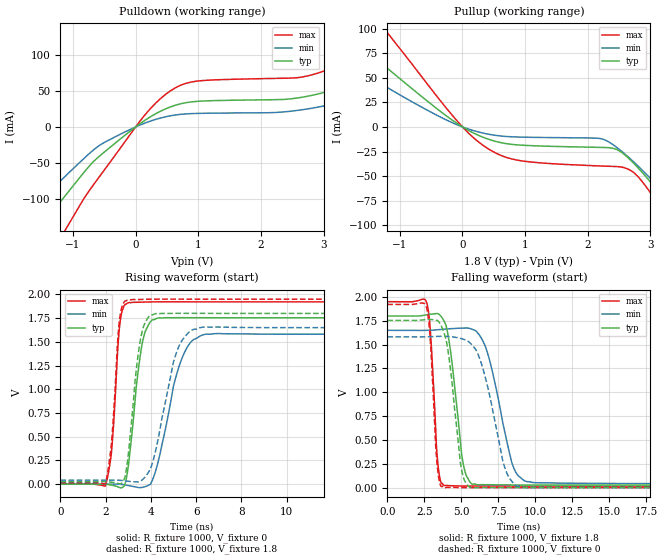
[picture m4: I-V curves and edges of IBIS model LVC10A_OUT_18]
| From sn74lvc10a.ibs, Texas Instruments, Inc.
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[Model]   LVC10A_OUT_18
Model_type  Output
Vref =   0
Rref =   1000
Cref =   30p
Vmeas =   0.9
| variable   typ   min   max
C_comp   6.87pF   4.46pF   11.31pF
| C_pullup   5.90pF   4.46pF   6.82pF
| C_pulldown   7.84pF   4.65pF   11.31pF
[Temperature Range]   40   100   -40
| Ambient temperature   25   85   -40
[Voltage range]   1.8   1.65   1.95
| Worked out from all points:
|   slope of the pulldown table from 0 to 0.27 V, typ, clamps not added: 17.1 ohm
|   slope of the pullup table from 0 to 0.27 V, typ, clamps not added: 29.9 ohm
|   rising waveform, R_fixture 1000, V_fixture 0: 20-80 % time 481ps typ, 877ps min, 294ps max; typ from 0 V to 1.75 V
|   falling waveform, R_fixture 1000, V_fixture 1.8: 20-80 % time 740ps typ, 1.33ns min, 389ps max; typ from 1.8 V to 0.027 V
|   rising waveform, R_fixture 1000, V_fixture 1.8: 20-80 % time 454ps typ, 830ps min, 301ps max; typ from 0.027 V to 1.8 V
|   falling waveform, R_fixture 1000, V_fixture 0: 20-80 % time 746ps typ, 1.33ns min, 384ps max; typ from 1.75 V to 0 V
[Pulldown]
| LVC10A_OUT_18
|   Voltage   I(typ)   I(min)   I(max)
-5.5V     -559.1mA   -452.2mA   -710.9mA
-2.18V    -208.5mA   -158.8mA   -285.4mA
-1.865V   -175.2mA   -131.6mA   -244.5mA
-1.48V    -133.9mA   -98.56mA   -193.1mA
-1.07V    -89.31mA   -63.76mA   -134.9mA
70mV      4.491mA    2.617mA    8.125mA
615mV     29.45mA    16.27mA    53.12mA
2.815V    43.69mA    25.92mA    72.1mA
4.325V    93.52mA    64.21mA    142.7mA
5.155V    134.5mA    96.03mA    199.6mA
6.155V    191.3mA    141.3mA    276.1mA
11V       510.2mA    405.2mA    689.3mA
[Pullup]
| LVC10A_OUT_18
|   Voltage   I(typ)   I(min)   I(max)
-5.5V     324.9mA    249.5mA    454.8mA
-2.68V    143.9mA    103mA      216.3mA
-2.015V   104.9mA    73.15mA    161.8mA
-1.32V    66.21mA    44.72mA    105.6mA
360mV     -11.3mA    -6.711mA   -20.18mA
985mV     -18.72mA   -10.42mA   -34.9mA
2.465V    -23.02mA   -20.97mA   -40.36mA
2.785V    -40.46mA   -38.76mA   -49.43mA
3.365V    -85.63mA   -77.45mA   -103.2mA
3.56V     -102.6mA   -91.66mA   -124.4mA
3.775V    -122mA     -107.8mA   -148.7mA
11V       -874.4mA   -739.7mA   -1.068A
[Ramp]
| LVC10A_OUT_18
| variable   typ   min   max
dV/dt_r   1.08/5.07E-10   0.97/9.81E-10   1.17/3.07E-10
dV/dt_f   1.08/8.15E-10   0.98/1.41E-09   1.18/4.18E-10
R_load = 1000
[Rising Waveform]
| LVC10A_OUT_18
R_fixture =   1000
C_fixture =   0
L_fixture =   0
V_fixture =   0
V_fixture_min = 0
V_fixture_max = 0
|   Time   V(typ)   V(min)   V(max)
0s        194.2pV    4.892nV    16.26pV
1.985ns   268.2uV    283.8uV    -20.06mV
2.255ns   -9.445mV   329uV      334.9mV
2.63ns    -36.22mV   -1.169mV   1.696V
3ns       192mV      -14.07mV   1.913V
3.615ns   1.483V     -33.44mV   1.919V
4.28ns    1.749V     200.5mV    1.922V
5.295ns   1.755V     1.279V     1.922V
6.32ns    1.755V     1.576V     1.922V
24.99ns   1.754V     1.581V     1.922V
[Falling Waveform]
| LVC10A_OUT_18
R_fixture =   1000
C_fixture =   0
L_fixture =   0
V_fixture =   1.8
V_fixture_min = 1.65
V_fixture_max = 1.95
|   Time   V(typ)   V(min)   V(max)
0s        1.8V       1.65V      1.95V
2.67ns    1.813V     1.65V      1.935V
2.93ns    1.819V     1.651V     1.596V
3.405ns   1.826V     1.656V     267.6mV
3.835ns   1.746V     1.662V     22.73mV
5.085ns   288.2mV    1.673V     16.58mV
5.72ns    37.23mV    1.662V     16.12mV
6.665ns   30.08mV    1.463V     16.19mV
9.27ns    27.45mV    71.42mV    16.27mV
24.99ns   27.13mV    42.43mV    16.27mV
[Rising Waveform]
| LVC10A_OUT_18
R_fixture =   1000
C_fixture =   0
L_fixture =   0
V_fixture =   1.8
V_fixture_min = 1.65
V_fixture_max = 1.95
|   Time   V(typ)   V(min)   V(max)
0s        27.13mV    42.42mV    16.27mV
1.985ns   27.29mV    42.61mV    2.873mV
2.25ns    20.96mV    42.58mV    415.8mV
2.61ns    4.817mV    41.38mV    1.73V
2.98ns    273mV      31.28mV    1.943V
3.545ns   1.535V     33.18mV    1.948V
4.175ns   1.796V     320.9mV    1.95V
5.06ns    1.801V     1.339V     1.95V
5.895ns   1.801V     1.632V     1.95V
24.99ns   1.8V       1.65V      1.95V
[Falling Waveform]
| LVC10A_OUT_18
R_fixture =   1000
C_fixture =   0
L_fixture =   0
V_fixture =   0
V_fixture_min = 0
V_fixture_max = 0
|   Time   V(typ)   V(min)   V(max)
0s        1.754V     1.581V     1.922V
2.65ns    1.763V     1.582V     1.889V
2.91ns    1.764V     1.583V     1.532V
3.335ns   1.754V     1.586V     296.4mV
3.65ns    1.694V     1.587V     9.418mV
4.155ns   1.377V     1.585V     1.461mV
4.985ns   215.1mV    1.564V     190.5uV
5.57ns    3.822mV    1.52V      -223.1uV
8.745ns   197.7uV    16.73mV    -1.986uV
24.99ns   5.329nV    2.403uV    13.48nV
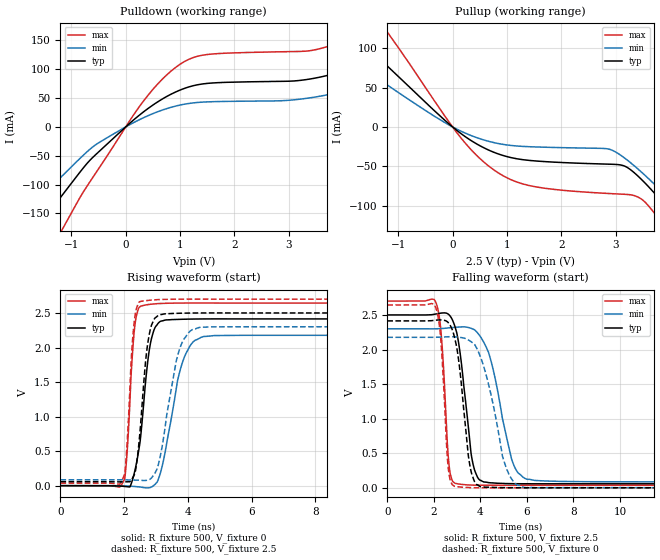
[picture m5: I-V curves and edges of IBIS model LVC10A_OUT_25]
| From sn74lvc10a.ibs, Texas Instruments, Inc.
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[Model]   LVC10A_OUT_25
Model_type  Output
Vref =   0
Rref =   500
Cref =   30p
Vmeas =   1.25
| variable   typ   min   max
C_comp   6.67pF   4.38pF   10.22pF
| C_pullup   5.84pF   4.42pF   6.92pF
| C_pulldown   7.51pF   4.38pF   10.22pF
[Temperature Range]   40   100   -40
| Ambient temperature   25   85   -40
[Voltage range]   2.5   2.3   2.7
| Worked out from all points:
|   slope of the pulldown table from 0 to 0.375 V, typ, clamps not added: 12.7 ohm
|   slope of the pullup table from 0 to 0.375 V, typ, clamps not added: 20 ohm
|   rising waveform, R_fixture 500, V_fixture 0: 20-80 % time 331ps typ, 536ps min, 194ps max; typ from 0 V to 2.41 V
|   falling waveform, R_fixture 500, V_fixture 2.5: 20-80 % time 482ps typ, 825ps min, 265ps max; typ from 2.5 V to 0.057 V
|   rising waveform, R_fixture 500, V_fixture 2.5: 20-80 % time 277ps typ, 487ps min, 187ps max; typ from 0.057 V to 2.5 V
|   falling waveform, R_fixture 500, V_fixture 0: 20-80 % time 446ps typ, 814ps min, 258ps max; typ from 2.41 V to 0 V
[Pulldown]
| LVC10A_OUT_25
|   Voltage   I(typ)   I(min)   I(max)
-5.5V     -598.1mA   -479.8mA   -766.5mA
-2.12V    -233mA     -174.4mA   -327.1mA
-1.575V   -168.1mA   -123.2mA   -244.7mA
-1.15V    -116.2mA   -83.21mA   -174.9mA
-565mV    -49.19mA   -31.72mA   -81.94mA
365mV     28.75mA    17.58mA    49.46mA
1.32V     73.05mA    42.4mA     122.5mA
4V        96.78mA    61.72mA    149.2mA
4.6V      117.3mA    77.78mA    177.9mA
5.77V     171.8mA    120.4mA    253.2mA
7.055V    245.3mA    179.5mA    351.5mA
11V       504.9mA    394.6mA    686.5mA
[Pullup]
| LVC10A_OUT_25
|   Voltage   I(typ)   I(min)   I(max)
-5.5V     363.4mA    279.9mA    508.8mA
-2.6V     169.4mA    122.6mA    251.6mA
-1.815V   117.7mA    83.03mA    179.1mA
-1.37V    88.47mA    61.37mA    136.9mA
170mV     -9.222mA   -5.867mA   -15.32mA
760mV     -32.2mA    -19.89mA   -54.58mA
2.905V    -47.35mA   -28.79mA   -84.65mA
3.45V     -65.04mA   -55.88mA   -90.57mA
3.92V     -100.7mA   -87.07mA   -129.3mA
4.19V     -123.8mA   -106.6mA   -157.6mA
4.495V    -151.4mA   -129.7mA   -191.8mA
11V       -830.2mA   -699.2mA   -1.022A
[Ramp]
| LVC10A_OUT_25
| variable   typ   min   max
dV/dt_r   1.46/3.64E-10   1.32/6.08E-10   1.60/2.04E-10
dV/dt_f   1.48/5.15E-10   1.35/8.62E-10   1.62/2.81E-10
R_load = 500
[Rising Waveform]
| LVC10A_OUT_25
R_fixture =   500
C_fixture =   0
L_fixture =   0
V_fixture =   0
V_fixture_min = 0
V_fixture_max = 0
|   Time   V(typ)   V(min)   V(max)
0s        177.7pV    3.876nV    17.91pV
2ns       -10.49mV   -2.208mV   83.96mV
2.095ns   -14.98mV   -4.472mV   506.8mV
2.325ns   196.9mV    -11.74mV   2.278V
2.61ns    1.177V     -27.32mV   2.61V
2.79ns    1.97V      -29.37mV   2.624V
2.99ns    2.306V     29.2mV     2.633V
3.825ns   2.409V     1.779V     2.644V
4.495ns   2.414V     2.16V      2.644V
24.99ns   2.414V     2.176V     2.644V
[Falling Waveform]
| LVC10A_OUT_25
R_fixture =   500
C_fixture =   0
L_fixture =   0
V_fixture =   2.5
V_fixture_min = 2.3
V_fixture_max = 2.7
|   Time   V(typ)   V(min)   V(max)
0s        2.5V       2.3V       2.7V
2.105ns   2.515V     2.3V       2.664V
2.335ns   2.528V     2.303V     2.14V
2.645ns   2.504V     2.313V     354.2mV
2.92ns    2.317V     2.321V     63.25mV
3.64ns    415.6mV    2.301V     38.86mV
4.14ns    83.94mV    2.108V     35.93mV
5.335ns   59.62mV    420.7mV    35.7mV
5.985ns   57.85mV    125.6mV    35.85mV
24.99ns   57.33mV    84.96mV    35.94mV
[Rising Waveform]
| LVC10A_OUT_25
R_fixture =   500
C_fixture =   0
L_fixture =   0
V_fixture =   2.5
V_fixture_min = 2.3
V_fixture_max = 2.7
|   Time   V(typ)   V(min)   V(max)
0s        57.33mV    84.96mV    35.94mV
1.965ns   55.36mV    84.47mV    110.1mV
2.07ns    55.91mV    83.66mV    459.5mV
2.295ns   138mV      81.31mV    2.281V
2.515ns   887.5mV    77.92mV    2.668V
2.715ns   1.977V     78.23mV    2.68V
2.93ns    2.401V     154.9mV    2.69V
3.715ns   2.496V     1.943V     2.7V
4.365ns   2.5V       2.292V     2.701V
24.99ns   2.5V       2.3V       2.7V
[Falling Waveform]
| LVC10A_OUT_25
R_fixture =   500
C_fixture =   0
L_fixture =   0
V_fixture =   0
V_fixture_min = 0
V_fixture_max = 0
|   Time   V(typ)   V(min)   V(max)
0s        2.414V     2.176V     2.644V
2.085ns   2.424V     2.177V     2.602V
2.305ns   2.428V     2.179V     2.111V
2.615ns   2.39V      2.184V     297.6mV
2.9ns     2.16V      2.183V     20.44mV
3.54ns    336.9mV    2.127V     2.531mV
4ns       16.37mV    1.896V     77.44uV
5.05ns    1.404mV    346.3mV    -293.3uV
5.87ns    -51.98uV   5.991mV    -72.33uV
24.99ns   17.86nV    42.93nV    1.212nV
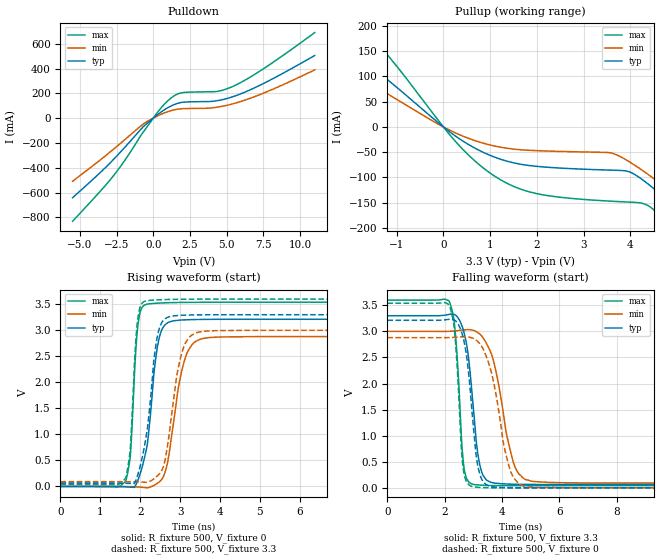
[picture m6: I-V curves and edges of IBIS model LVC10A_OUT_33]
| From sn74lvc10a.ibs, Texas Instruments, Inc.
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[Model]   LVC10A_OUT_33
Model_type  Output
Vref =   0
Rref =   500
Cref =   50p
Vmeas =   1.5
| variable   typ   min   max
C_comp   6.31pF   3.46pF   9.45pF
| C_pullup   5.72pF   3.46pF   7.15pF
| C_pulldown   6.91pF   4.18pF   9.45pF
[Temperature Range]   40   100   -40
| Ambient temperature   25   85   -40
[Voltage range]   3.3   3   3.6
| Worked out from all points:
|   slope of the pulldown table from 0 to 0.495 V, typ, clamps not added: 10.7 ohm
|   slope of the pullup table from 0 to 0.495 V, typ, clamps not added: 15.2 ohm
|   rising waveform, R_fixture 500, V_fixture 0: 20-80 % time 275ps typ, 355ps min, 146ps max; typ from 0 V to 3.21 V
|   falling waveform, R_fixture 500, V_fixture 3.3: 20-80 % time 349ps typ, 600ps min, 226ps max; typ from 3.3 V to 0.065 V
|   rising waveform, R_fixture 500, V_fixture 3.3: 20-80 % time 290ps typ, 331ps min, 145ps max; typ from 0.065 V to 3.3 V
|   falling waveform, R_fixture 500, V_fixture 0: 20-80 % time 342ps typ, 583ps min, 217ps max; typ from 3.21 V to 0 V
[Pulldown]
| LVC10A_OUT_33
|   Voltage   I(typ)   I(min)   I(max)
-5.5V     -642.1mA   -509.2mA   -832.1mA
-3.645V   -442.6mA   -340.3mA   -594.1mA
-2.71V    -333.2mA   -250.5mA   -464.6mA
-1.885V   -228.4mA   -168.1mA   -330.7mA
-620mV    -62.4mA    -41.49mA   -102.1mA
455mV     42.83mA    26.93mA    71.74mA
1.215V    98.07mA    60.46mA    162.3mA
1.91V     125.9mA    75.23mA    203.5mA
4.31V     139.6mA    87.57mA    214.6mA
5.45V     173.8mA    116.3mA    257.3mA
7.53V     280.4mA    202.4mA    399.9mA
11V       505.3mA    389mA      689.8mA
[Pullup]
| LVC10A_OUT_33
|   Voltage   I(typ)   I(min)   I(max)
-5.5V     404.4mA    310.8mA    569.2mA
-3.515V   265mA      197.3mA    383.4mA
-2.48V    190.1mA    138.3mA    280.1mA
-1.635V   127.1mA    90.28mA    191.1mA
505mV     -33.05mA   -21.44mA   -52.79mA
1.855V    -76.61mA   -46.34mA   -128.9mA
3.7V      -85.85mA   -55.1mA    -147.6mA
4.24V     -103.3mA   -84.95mA   -151mA
4.895V    -154.7mA   -130.6mA   -201.2mA
5.365V    -197.4mA   -166.8mA   -253mA
5.825V    -241.6mA   -203.9mA   -307.6mA
11V       -786.6mA   -661.2mA   -974mA
[Ramp]
| LVC10A_OUT_33
| variable   typ   min   max
dV/dt_r   1.94/3.00E-10   1.74/3.73E-10   2.13/1.49E-10
dV/dt_f   1.96/3.68E-10   1.76/6.30E-10   2.15/2.46E-10
R_load = 500
[Rising Waveform]
| LVC10A_OUT_33
R_fixture =   500
C_fixture =   0
L_fixture =   0
V_fixture =   0
V_fixture_min = 0
V_fixture_max = 0
|   Time   V(typ)   V(min)   V(max)
0s        184.9pV    3.596nV    20.95pV
1.64ns    -7.5mV     -3.094mV   107.6mV
1.75ns    -12.81mV   -4.432mV   570.3mV
1.945ns   125.9mV    -10.74mV   3.119V
2.175ns   791.9mV    -27.54mV   3.504V
2.38ns    2.405V     35.22mV    3.52V
2.545ns   3.017V     142.1mV    3.527V
3.1ns     3.201V     2.395V     3.537V
3.565ns   3.21V      2.843V     3.539V
24.99ns   3.212V     2.88V      3.539V
[Falling Waveform]
| LVC10A_OUT_33
R_fixture =   500
C_fixture =   0
L_fixture =   0
V_fixture =   3.3
V_fixture_min = 3
V_fixture_max = 3.6
|   Time   V(typ)   V(min)   V(max)
0s        3.3V       3V         3.6V
2.16ns    3.326V     3.001V     3.578V
2.375ns   3.313V     3.01V      2.958V
2.67ns    2.992V     3.028V     411.2mV
2.965ns   1.756V     3.026V     72.31mV
3.355ns   227.4mV    2.866V     49.17mV
3.74ns    90.55mV    2.358V     43.05mV
4.395ns   68.86mV    494.8mV    41.52mV
5.005ns   64.64mV    130.6mV    41.63mV
24.99ns   64.52mV    92.1mV     41.93mV
[Rising Waveform]
| LVC10A_OUT_33
R_fixture =   500
C_fixture =   0
L_fixture =   0
V_fixture =   3.3
V_fixture_min = 3
V_fixture_max = 3.6
|   Time   V(typ)   V(min)   V(max)
0s        64.52mV    92.1mV     41.93mV
1.64ns    59.73mV    90.44mV    164.8mV
1.75ns    57.36mV    89.73mV    713.6mV
1.935ns   214.7mV    86.78mV    3.193V
2.17ns    1.055V     78.18mV    3.57V
2.355ns   2.51V      152.7mV    3.583V
2.52ns    3.119V     279.8mV    3.589V
3.05ns    3.291V     2.582V     3.598V
3.565ns   3.299V     2.978V     3.6V
24.99ns   3.3V       3V         3.6V
[Falling Waveform]
| LVC10A_OUT_33
R_fixture =   500
C_fixture =   0
L_fixture =   0
V_fixture =   0
V_fixture_min = 0
V_fixture_max = 0
|   Time   V(typ)   V(min)   V(max)
0s        3.212V     2.88V      3.539V
2.16ns    3.231V     2.881V     3.504V
2.36ns    3.212V     2.887V     2.922V
2.65ns    2.877V     2.896V     366.6mV
2.99ns    1.256V     2.869V     20.01mV
3.155ns   431.9mV    2.805V     10.91mV
3.39ns    92.65mV    2.608V     4.521mV
4.265ns   3.543mV    377.2mV    -506.8uV
4.87ns    -301.2uV   21.2mV     -334.9uV
24.99ns   13.69nV    1.992nV    5.128nV
